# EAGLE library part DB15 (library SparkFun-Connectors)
DB15 / VGA right angle through-hole female connector.

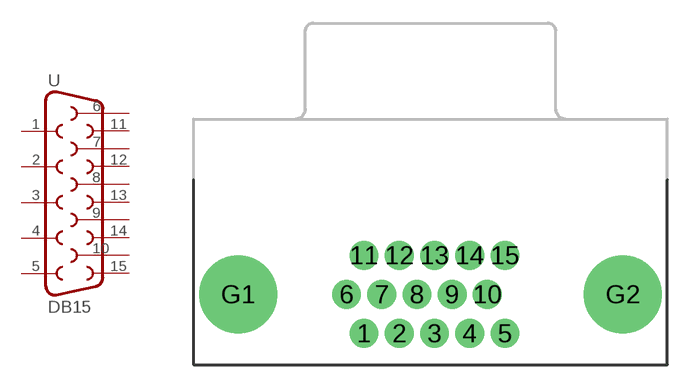
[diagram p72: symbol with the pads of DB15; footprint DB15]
Designator prefix -

## DB15  [DB15]
1  1  pas
2  2  pas
3  3  pas
4  4  pas
5  5  pas
6  6  pas
7  7  pas
8  8  pas
9  9  pas
10  10  pas
11  11  pas
12  12  pas
13  13  pas
14  14  pas
15  15  pas

## Footprint DB15 (pad centres in mm)
drill 1.016 pad 1.88: 1 -4.32,-7.62; 2 -2.03,-7.62; 3 0.26,-7.62; 4 2.55,-7.62; 5 4.84,-7.62; 6 -5.46,-5.08; 7 -3.17,-5.08; 8 -0.88,-5.08; 9 1.41,-5.08; 10 3.7,-5.08; 11 -4.32,-2.54; 12 -2.03,-2.54; 13 0.26,-2.54; 14 2.55,-2.54; 15 4.84,-2.54
drill 3.302 pad 5.08: G1 -12.5,-5.08; G2 12.5,-5.08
